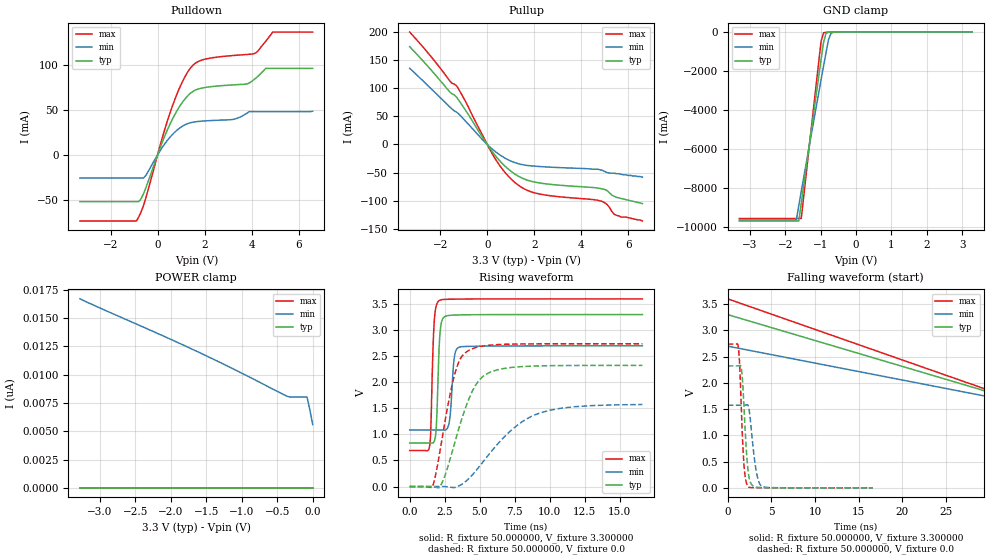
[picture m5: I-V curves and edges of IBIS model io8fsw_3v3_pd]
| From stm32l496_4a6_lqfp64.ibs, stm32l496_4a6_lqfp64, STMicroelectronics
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|   Model io8fsw_3v3_pd
[Model]  io8fsw_3v3_pd
Model_type I/O
Polarity   Non-Inverting
Enable   Active-Low
Vinl =   0.990000V
Vinh =   2.310000V
Vmeas =  1.650000V
Cref =   100.000000nF
Rref =   1.000000k
Vref =   3.300000V
C_comp   2.968600pF   2.938100pF   3.196200pF
[Temperature Range]   25.000000   0.125000k   -40.000000
[Pullup Reference]   3.300000V   2.700000V   3.600000V
[Pulldown Reference]   0.0V   0.0V   0.0V
[POWER Clamp Reference]   3.300000V   2.700000V   3.600000V
[GND Clamp Reference]   0.0V   0.0V   0.0V
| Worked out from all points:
|   slope of the pulldown table from 0 to 0.495 V, typ, clamps not added: 15.4 ohm
|   slope of the pullup table from 0 to 0.495 V, typ, clamps not added: 18.1 ohm
|   GND clamp passes 1 mA (typ) near -0.58 V on its own axis
|   rising waveform, R_fixture 50.000000, V_fixture 3.300000: 20-80 % time 197ps typ, 239ps min, 194ps max; typ from 0.835 V to 3.3 V
|   rising waveform, R_fixture 50.000000, V_fixture 0.0: 20-80 % time 1.71ns typ, 3.36ns min, 1.18ns max; typ from 0 V to 2.32 V
|   falling waveform, R_fixture 50.000000, V_fixture 3.300000: 20-80 % time 30ns typ, 30ns min, 30ns max; typ from 3.3 V to 0.835 V
|   falling waveform, R_fixture 50.000000, V_fixture 0.0: 20-80 % time 487ps typ, 658ps min, 409ps max; typ from 2.32 V to 0 V
[Pulldown]
|Voltage   I(typ)   I(min)   I(max)
-3.3V     -51.63mA   -25.53mA   -73.04mA
-900mV    -51.63mA   -25.53mA   -73.04mA
-500mV    -36.51mA   -22.79mA   -47.71mA
200mV     14.02mA    8.316mA    18.9mA
700mV     42.99mA    24.4mA     58.9mA
1.2V      63.06mA    33.8mA     88.14mA
1.6V      71.63mA    36.67mA    101.4mA
3.2V      77.51mA    39.29mA    110mA
4.1V      83.27mA    47.97mA    111.9mA
4.6V      95.8mA     47.97mA    125.7mA
4.9V      95.8mA     47.97mA    136mA
6.6V      95.8mA     48.43mA    136mA
[Pullup]
|Voltage   I(typ)   I(min)   I(max)
-3.3V     173.7mA    135.4mA    199.7mA
-1.6V     93.6mA     66.95mA    113.2mA
-1.3V     83.81mA    57.29mA    104.1mA
300mV     -17.49mA   -11.19mA   -22.71mA
700mV     -36.32mA   -22.9mA    -46.84mA
1.2V      -53.2mA    -32.62mA   -68.34mA
1.7V      -63.36mA   -37.25mA   -81.47mA
2.2V      -68.23mA   -39.11mA   -87.81mA
4.8V      -78.1mA    -45mA      -100.2mA
5.1V      -82mA      -50mA      -106.7mA
5.5V      -94mA      -52mA      -126mA
6.6V      -105mA     -58mA      -136mA
[GND_clamp]
|Voltage   I(typ)   I(min)   I(max)
-3.3V     -9.687A    -9.633A    -9.557A
-1.69V    -9.687A    -9.633A    -9.557A
-1.62V    -9.687A    -8.894A    -9.557A
-1.55V    -8.764A    -8.167A    -9.557A
-1.13V    -3.236A    -3.867A    -2.713A
-990mV    -1.417A    -2.448A    -480.2mA
-920mV    -530mA     -1.746A    -39.97mA
-850mV    -62.37mA   -1.055A    -14.05mA
-780mV    -12.06mA   -390.4mA   -9.024mA
-710mV    -4.91mA    -69.1mA    -5.331mA
-640mV    -2.318mA   -14.6mA    -2.508mA
3.28V     87.11uA    88.99uA    71.58uA
[POWER_clamp]
|Voltage   I(typ)   I(min)   I(max)
-3.28V    0A         16.68nA    0A
-1.64V    0A         12.07nA    0A
-1.08V    0A         10.37nA    0A
-360mV    0A         8.078nA    0A
-320mV    0A         8.02nA     0A
-80mV     0A         8.02nA     0A
-40mV     0A         6.883nA    0A
0V        0A         5.582nA    0A
[Ramp]
| variable   typ   min   max
dV/dt_r  1.39404/1.70972n   0.94416/3.38277n   1.64262/1.17724n
dV/dt_f  1.47854/1.57846n   0.96744/3.12694n   1.74566/1.07839n
R_load = 50.000000
[Rising Waveform]
R_fixture= 50.000000
V_fixture= 3.300000
V_fixture_min= 2.700000
V_fixture_max= 3.600000
|time   V(typ)   V(min)   V(max)
0s        834.7mV    1.086V     689.8mV
1.401ns   834.2mV    1.086V     741.1mV
1.502ns   833.6mV    1.086V     1.046V
1.702ns   843mV      1.086V     2.91V
1.869ns   1.023V     1.086V     3.433V
2.102ns   2.659V     1.085V     3.565V
2.803ns   3.281V     1.204V     3.592V
3.17ns    3.289V     2.441V     3.594V
3.537ns   3.292V     2.672V     3.595V
16.62ns   3.299V     2.699V     3.599V
[Rising Waveform]
R_fixture= 50.000000
V_fixture= 0.0
V_fixture_min= 0.0
V_fixture_max= 0.0
|time   V(typ)   V(min)   V(max)
0s        3.724nV    95.34nV    3.47nV
1.635ns   -3.464mV   928.1nV    1.076mV
2.236ns   33.71mV    192.3uV    793.3mV
3.136ns   762.5mV    -19.66mV   2.072V
3.604ns   1.197V     24.39mV    2.444V
4.104ns   1.594V     122.1mV    2.593V
5.439ns   2.151V     541.6mV    2.703V
7.174ns   2.28V      1.06V      2.731V
8.942ns   2.311V     1.376V     2.736V
16.62ns   2.323V     1.574V     2.738V
[Falling Waveform]
R_fixture= 50.000000
V_fixture= 3.300000
V_fixture_min= 2.700000
V_fixture_max= 3.600000
|time   V(typ)   V(min)   V(max)
0s        3.299V     2.699V     3.599V
50.05ns   834.7mV    1.086V     689.8mV
100.1ns   834.7mV    1.086V     689.8mV
4.955us   834.7mV    1.086V     689.8mV
[Falling Waveform]
R_fixture= 50.000000
V_fixture= 0.0
V_fixture_min= 0.0
V_fixture_max= 0.0
|time   V(typ)   V(min)   V(max)
0s        2.323V     1.574V     2.738V
1.201ns   2.323V     1.574V     2.694V
1.368ns   2.328V     1.574V     2.338V
1.568ns   2.261V     1.574V     1.466V
1.835ns   1.631V     1.573V     500.9mV
2.102ns   801mV      1.578V     122.4mV
2.336ns   322.7mV    1.569V     21.6mV
3.237ns   14.39mV    348.5mV    2.475mV
3.871ns   6.054mV    33.44mV    1.808mV
16.62ns   3.724nV    95.34nV    3.47nV
